! (c) 2009  Infineon Technologies AG, Munich
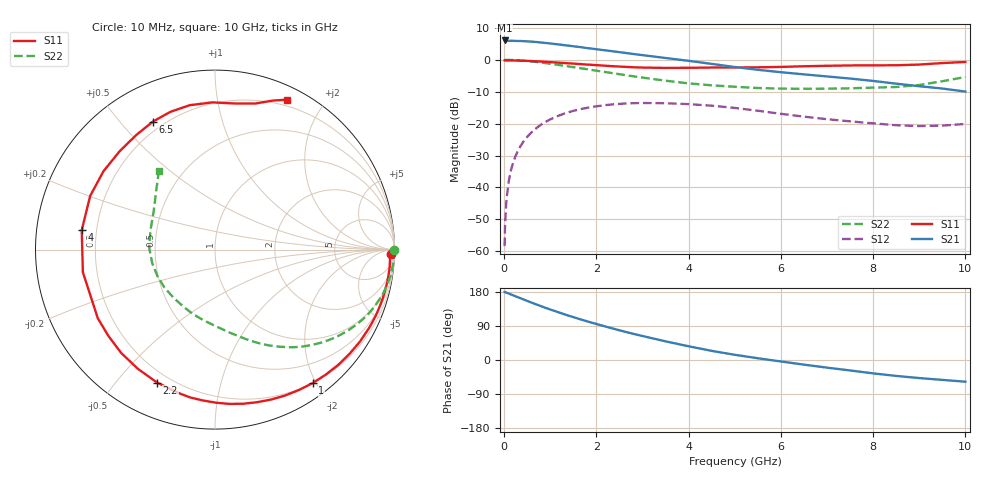
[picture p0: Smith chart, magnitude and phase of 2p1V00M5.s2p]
! Infineon Technologies  Discrete & RF Semiconductors
! BFP420
! VCE =  1.0 V,  IC =  0.5 mA
! Common Emitter S-Parameters:  Nov 2009
# GHz  S  MA  R  50
!  f  S11  S21  S12  S22
! GHz  MAG  ANG  MAG  ANG  MAG  ANG  MAG  ANG
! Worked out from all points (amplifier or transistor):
!   46 points, 10 MHz to 10 GHz, reference 50 ohm
!   highest |S21| = 6.1 dB at 10 MHz (marker M1)
!   |S21| within 3 dB of that: start of sweep to 2.14 GHz
!   unconditionally stable (mu >= 1): 4.398 GHz to end of sweep
!   at 300 MHz: K = 0.03, MSG = 17.2 dB, |S12| = -28.5 dB
!   at 1.7 GHz: K = 0.31, MSG = 9.6 dB, |S12| = -15.3 dB
!   at 10 GHz: K = 1.55, MAG = 0.7 dB, |S12| = -20.1 dB
!   lowest NFmin = 0.68 dB at 900 MHz
!   S11 on the Smith chart (normalised r, x): 10 MHz: 35, -54; 1 GHz: 0.20, -1.96; 2.2 GHz: 0.15, -0.65; 4 GHz: 0.14, +0.07; 6.5 GHz: 0.16, +0.61; 10 GHz: 0.13, +1.58
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0.01  0.9833 -1.5  2.013 179.4  0.0012 84.7  0.9981 -0.2
0.02  0.9795 -1.0  1.963 179.6  0.0026 88.8  0.9978 -0.6
0.05  0.9763 -2.7  1.975 177.5  0.0064 87.3  0.9978 -1.7
0.1  0.978 -5.4  1.986 175.4  0.0126 87.2  0.9968 -3.4
0.15  0.9774 -8.1  1.988 172.9  0.0189 84.9  0.9946 -5.1
0.2  0.9766 -10.7  1.987 170.5  0.0252 83.1  0.9916 -6.8
0.35  0.971 -18.8  1.976 163.2  0.0439 77.8  0.9781 -11.8
0.5  0.9634 -26.9  1.949 155.9  0.0621 72.3  0.9584 -16.7
0.7  0.9481 -37.8  1.902 146.5  0.0853 65.0  0.9257 -22.9
1  0.9215 -53.8  1.806 133.3  0.1166 54.7  0.8678 -31.3
1.4  0.8819 -74.6  1.666 116.9  0.1511 41.8  0.7877 -41.1
1.7  0.853 -89.6  1.567 105.6  0.1715 32.8  0.7303 -47.6
2.2  0.808 -113.5  1.408 88.2  0.1952 19.1  0.6428 -57.2
2.8  0.7642 -141.0  1.235 69.1  0.2091 3.8  0.5525 -67.7
3.5  0.7469 -170.3  1.069 49.2  0.2089 -11.6  0.4706 -79.8
4  0.7503 171.7  0.965 36.2  0.2021 -20.8  0.4277 -89.2
4.5  0.757 156.7  0.864 24.1  0.1912 -29.3  0.3986 -99.4
5.5  0.7632 134.2  0.698 4.6  0.1592 -42.0  0.3619 -120.2
6.5  0.7927 115.9  0.592 -12.2  0.1287 -47.7  0.3522 -142.9
7  0.8069 107.9  0.549 -20.2  0.1174 -48.1  0.3531 -154.8
8.5  0.8216 82.2  0.423 -42.0  0.0944 -43.6  0.3751 163.4
10  0.9262 64.4  0.318 -57.3  0.0989 -30.9  0.538 125.5
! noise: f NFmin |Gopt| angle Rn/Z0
0.9  0.68  0.78  35  0.65
1.8  1.42  0.6  75  0.5
2.4  1.57  0.58  98  0.37
3  2.1  0.58  128  0.24
4  2.49  0.57  177  0.09
